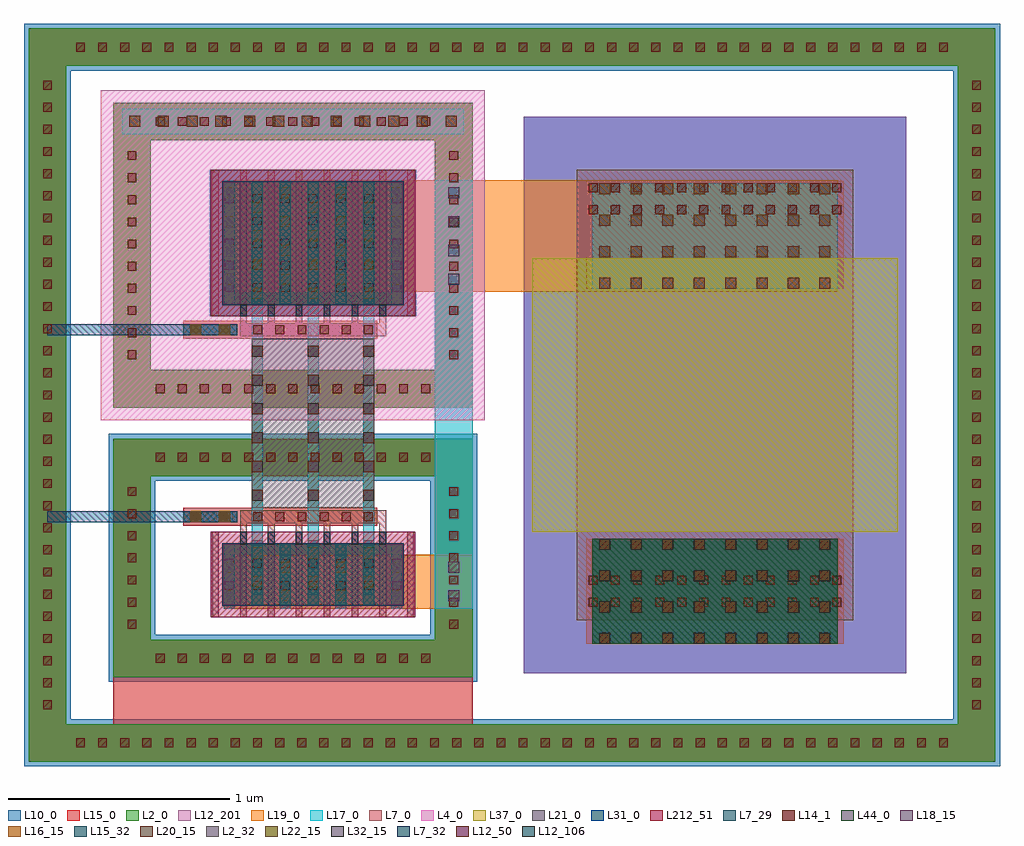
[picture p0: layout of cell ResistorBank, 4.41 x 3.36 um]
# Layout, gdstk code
import gdstk
lib = gdstk.Library(unit=1e-6, precision=1e-09)
def R(c, l, rs):  # rectangles x0, y0, x1, y1
    for r in rs: c.add(gdstk.rectangle(r[:2], r[2:], *l))
def A(c, l, x, y, w, h, nx, ny, dx, dy):  # array of equal rectangles
    R(c, l, [(x+i*dx, y+j*dy, x+i*dx+w, y+j*dy+h) for i in range(nx) for j in range(ny)])
def P(c, l, *ps):  # polygons
    for p in ps: c.add(gdstk.Polygon(p, *l))
L2_0 = (2, 0)
L2_32 = (2, 32)
L4_0 = (4, 0)
L7_0 = (7, 0)
L7_29 = (7, 29)
L7_32 = (7, 32)
L10_0 = (10, 0)
L12_50 = (12, 50)
L12_106 = (12, 106)
L12_201 = (12, 201)
L14_1 = (14, 1)
L15_0 = (15, 0)
L15_32 = (15, 32)
L16_15 = (16, 15)
L17_0 = (17, 0)
L18_15 = (18, 15)
L19_0 = (19, 0)
L20_15 = (20, 15)
L21_0 = (21, 0)
L22_15 = (22, 15)
L31_0 = (31, 0)
L32_15 = (32, 15)
L37_0 = (37, 0)
L44_0 = (44, 0)
L212_51 = (212, 51)

viamet12met2oninputinres = lib.new_cell('ViaMet12Met2OnInputInResistorBank')
R(viamet12met2oninputinres, L15_0, [(-0.122,-0.025,0.122,0.025)])
R(viamet12met2oninputinres, L16_15, [(-0.09,-0.025,-0.04,0.025), (0.04,-0.025,0.09,0.025)])
R(viamet12met2oninputinres, L17_0, [(-0.122,-0.025,0.122,0.025)])

viamet12met2onvddinresis = lib.new_cell('ViaMet12Met2OnVDDInResistorBank')
R(viamet12met2onvddinresis, L15_0, [(-0.772,-0.057,0.772,0.057)])
A(viamet12met2onvddinresis, L16_15, -0.74, -0.025, 0.05, 0.05, 12, 1, 0.13, 0)
R(viamet12met2onvddinresis, L17_0, [(-0.772,-0.057,0.772,0.057)])

viavcmmet22met3inresisto = lib.new_cell('ViaVCMMet22Met3InResistorBank')
R(viavcmmet22met3inresisto, L17_0, [(-0.025,-0.382,0.025,0.382)])
A(viavcmmet22met3inresisto, L18_15, -0.025, -0.35, 0.05, 0.05, 1, 6, 0, 0.13)
R(viavcmmet22met3inresisto, L19_0, [(-0.025,-0.382,0.025,0.382)])

viamet52met6onresistorin = lib.new_cell('ViaMet52Met6OnResistorInResistorBank')
R(viamet52met6onresistorin, L31_0, [(-0.554,-0.238,0.554,0.238)])
A(viamet52met6onresistorin, L32_15, -0.522, -0.238, 0.05, 0.05, 8, 4, 0.142, 0.142)
R(viamet52met6onresistorin, L44_0, [(-0.554,-0.238,0.554,0.238)])

viatgnmos2resmet22met3in = lib.new_cell('ViaTGNMOS2ResMet22Met3InResistorBank')
R(viatgnmos2resmet22met3in, L17_0, [(-0.057,-0.09,0.057,0.09)])
R(viatgnmos2resmet22met3in, L18_15, [(-0.025,-0.09,0.025,-0.04), (-0.025,0.04,0.025,0.09)])
R(viatgnmos2resmet22met3in, L19_0, [(-0.057,-0.09,0.057,0.09)])

viamet32met4oninputinres = lib.new_cell('ViaMet32Met4OnInputInResistorBank')
R(viamet32met4oninputinres, L19_0, [(-0.122,-0.025,0.122,0.025)])
R(viamet32met4oninputinres, L20_15, [(-0.09,-0.025,-0.04,0.025), (0.04,-0.025,0.09,0.025)])
R(viamet32met4oninputinres, L21_0, [(-0.122,-0.025,0.122,0.025)])

viamet22met3oninputinres = lib.new_cell('ViaMet22Met3OnInputInResistorBank')
R(viamet22met3oninputinres, L17_0, [(-0.122,-0.025,0.122,0.025)])
R(viamet22met3oninputinres, L18_15, [(-0.09,-0.025,-0.04,0.025), (0.04,-0.025,0.09,0.025)])
R(viamet22met3oninputinres, L19_0, [(-0.122,-0.025,0.122,0.025)])

viamet12met2onresistorin = lib.new_cell('ViaMet12Met2OnResistorInResistorBank')
R(viamet12met2onresistorin, L15_0, [(-0.554,-0.238,0.554,0.238)])
A(viamet12met2onresistorin, L16_15, -0.522, -0.238, 0.05, 0.05, 8, 4, 0.142, 0.142)
R(viamet12met2onresistorin, L17_0, [(-0.554,-0.238,0.554,0.238)])

nmossubringinresistorban = lib.new_cell('NMOSSubringInResistorBank')
R(nmossubringinresistorban, L2_0, [(-0.812,-0.539,-0.642,0.539), (-0.812,-0.539,0.812,-0.369), (0.642,-0.539,0.812,0.539), (-0.812,0.369,0.812,0.539)])
A(nmossubringinresistorban, L14_1, -0.62, -0.474, 0.04, 0.04, 13, 2, 0.1, 0.908)
A(nmossubringinresistorban, L14_1, -0.747, -0.32, 0.04, 0.04, 1, 7, 0, 0.1)
A(nmossubringinresistorban, L14_1, 0.707, -0.32, 0.04, 0.04, 1, 7, 0, 0.1)
R(nmossubringinresistorban, L15_0, [(-0.812,-0.539,0.812,-0.369), (-0.812,-0.539,-0.642,0.539), (0.642,-0.539,0.812,0.539), (-0.812,0.369,0.812,0.539)])
nmossubringinresistorban.add(gdstk.FlexPath([(0.727,0.56),(0.727,-0.454),(-0.727,-0.454),(-0.727,0.454),(0.833,0.454)], 0.212, ends="flush", simple_path=True, layer=10, datatype=0))  # L10_0

totalsubringinresistorba = lib.new_cell('TotalSubringInResistorBank')
R(totalsubringinresistorba, L2_0, [(-2.184,-1.657,-2.014,1.657), (-2.184,-1.657,2.184,-1.487), (2.014,-1.657,2.184,1.657), (-2.184,1.487,2.184,1.657)])
A(totalsubringinresistorba, L14_1, -1.97, -1.592, 0.04, 0.04, 40, 2, 0.1, 3.144)
A(totalsubringinresistorba, L14_1, -2.119, -1.42, 0.04, 0.04, 1, 29, 0, 0.1)
A(totalsubringinresistorba, L14_1, 2.079, -1.42, 0.04, 0.04, 1, 29, 0, 0.1)
R(totalsubringinresistorba, L15_0, [(-2.184,-1.657,2.184,-1.487), (-2.184,-1.657,-2.014,1.657), (2.014,-1.657,2.184,1.657), (-2.184,1.487,2.184,1.657)])
totalsubringinresistorba.add(gdstk.FlexPath([(2.099,1.678),(2.099,-1.572),(-2.099,-1.572),(-2.099,1.572),(2.205,1.572)], 0.212, ends="flush", simple_path=True, layer=10, datatype=0))  # L10_0

opppcresinresistorbank = lib.new_cell('OpppcresInResistorBank')
R(opppcresinresistorbank, L7_0, [(-0.625,-1.017,0.625,1.017)])
R(opppcresinresistorbank, L10_0, [(-0.865,-1.257,0.865,1.257)])
R(opppcresinresistorbank, L12_201, [(-0.865,-1.257,0.865,1.257)])
A(opppcresinresistorbank, L14_1, -0.57, -0.957, 0.04, 0.04, 12, 2, 0.1, 0.1)
A(opppcresinresistorbank, L14_1, -0.57, 0.817, 0.04, 0.04, 12, 2, 0.1, 0.1)
R(opppcresinresistorbank, L15_0, [(-0.582,-0.969,0.582,-0.805), (-0.582,0.805,0.582,0.969)])
R(opppcresinresistorbank, L37_0, [(-0.825,-0.617,0.825,0.617)])

viatgpmos2resmet22met3in = lib.new_cell('ViaTGPMOS2ResMet22Met3InResistorBank')
R(viatgpmos2resmet22met3in, L17_0, [(-0.057,-0.22,0.057,0.22)])
A(viatgpmos2resmet22met3in, L18_15, -0.025, -0.22, 0.05, 0.05, 1, 4, 0, 0.13)
R(viatgpmos2resmet22met3in, L19_0, [(-0.057,-0.22,0.057,0.22)])

viamet42met5oninputinres = lib.new_cell('ViaMet42Met5OnInputInResistorBank')
R(viamet42met5oninputinres, L21_0, [(-0.122,-0.025,0.122,0.025)])
R(viamet42met5oninputinres, L22_15, [(-0.09,-0.025,-0.04,0.025), (0.04,-0.025,0.09,0.025)])
R(viamet42met5oninputinres, L31_0, [(-0.122,-0.025,0.122,0.025)])

pmossubringinresistorban = lib.new_cell('PMOSSubringInResistorBank')
R(pmossubringinresistorban, L2_0, [(-0.812,-0.689,-0.642,0.689), (-0.812,-0.689,0.812,-0.519), (0.642,-0.689,0.812,0.689), (-0.812,0.519,0.812,0.689)])
A(pmossubringinresistorban, L14_1, -0.62, -0.624, 0.04, 0.04, 13, 2, 0.1, 1.208)
A(pmossubringinresistorban, L14_1, -0.747, -0.47, 0.04, 0.04, 1, 10, 0, 0.1)
A(pmossubringinresistorban, L14_1, 0.707, -0.47, 0.04, 0.04, 1, 10, 0, 0.1)
R(pmossubringinresistorban, L15_0, [(-0.812,-0.689,0.812,-0.519), (-0.812,-0.689,-0.642,0.689), (0.642,-0.689,0.812,0.689), (-0.812,0.519,0.812,0.689)])
pmossubringinresistorban.add(gdstk.FlexPath([(0.727,0.745),(0.727,-0.604),(-0.727,-0.604),(-0.727,0.604),(0.868,0.604)], 0.282, ends="flush", simple_path=True, layer=4, datatype=0))  # L4_0

viavcmmet32met4inresisto = lib.new_cell('ViaVCMMet32Met4InResistorBank')
R(viavcmmet32met4inresisto, L19_0, [(-0.025,-0.382,0.025,0.382)])
A(viavcmmet32met4inresisto, L20_15, -0.025, -0.35, 0.05, 0.05, 1, 6, 0, 0.13)
R(viavcmmet32met4inresisto, L21_0, [(-0.025,-0.382,0.025,0.382)])

viamet12met2onnmosoutput = lib.new_cell('ViaMet12Met2OnNMOSOutputInTransmissionGate')
R(viamet12met2onnmosoutput, L15_0, [(-0.025,-0.122,0.025,0.122)])
R(viamet12met2onnmosoutput, L16_15, [(-0.025,-0.09,0.025,-0.04), (-0.025,0.04,0.025,0.09)])
R(viamet12met2onnmosoutput, L17_0, [(-0.025,-0.122,0.025,0.122)])

pmosintransmissiongate = lib.new_cell('PMOSInTransmissionGate')
R(pmosintransmissiongate, L2_0, [(-0.406,-0.275,0.406,0.275)])
R(pmosintransmissiongate, L2_32, [(-0.406,-0.275,-0.33,0.275), (0.33,-0.275,0.406,0.275)])
A(pmosintransmissiongate, L7_0, -0.456, -0.331, 0.03, 0.662, 8, 1, 0.126, 0)
R(pmosintransmissiongate, L7_29, [(-0.411,-0.28,0.411,0.28)])
A(pmosintransmissiongate, L7_32, -0.33, -0.331, 0.03, 0.056, 6, 1, 0.126, 0)
R(pmosintransmissiongate, L10_0, [(-0.466,-0.331,0.466,0.331)])
P(pmosintransmissiongate, L12_50, [(0,0),(0,0),(0,0),(0,0)])
P(pmosintransmissiongate, L12_106, [(0,0),(0,0),(0,0),(0,0)])
A(pmosintransmissiongate, L14_1, -0.398, -0.22, 0.04, 0.04, 7, 5, 0.126, 0.1)
A(pmosintransmissiongate, L15_0, -0.403, -0.275, 0.05, 0.55, 7, 1, 0.126, 0)
A(pmosintransmissiongate, L15_32, -0.403, -0.275, 0.05, 0.55, 7, 1, 0.126, 0)
R(pmosintransmissiongate, L212_51, [(-0.462,-0.331,0.462,0.331)])

viamet22met3onnmosoutput = lib.new_cell('ViaMet22Met3OnNMOSOutputInTransmissionGate')
R(viamet22met3onnmosoutput, L17_0, [(-0.025,-0.122,0.025,0.122)])
R(viamet22met3onnmosoutput, L18_15, [(-0.025,-0.09,0.025,-0.04), (-0.025,0.04,0.025,0.09)])
R(viamet22met3onnmosoutput, L19_0, [(-0.025,-0.122,0.025,0.122)])

viapoly2met1onnmoscontro = lib.new_cell('ViaPoly2Met1OnNMOSControlInTransmissionGate')
R(viapoly2met1onnmoscontro, L7_0, [(-0.28,-0.03,0.28,0.03)])
A(viapoly2met1onnmoscontro, L14_1, -0.27, -0.02, 0.04, 0.04, 6, 1, 0.1, 0)
R(viapoly2met1onnmoscontro, L15_0, [(-0.291,-0.041,0.291,0.041)])

viamet12met2onpmosoutput = lib.new_cell('ViaMet12Met2OnPMOSOutputInTransmissionGate')
R(viamet12met2onpmosoutput, L15_0, [(-0.025,-0.252,0.025,0.252)])
A(viamet12met2onpmosoutput, L16_15, -0.025, -0.22, 0.05, 0.05, 1, 4, 0, 0.13)
R(viamet12met2onpmosoutput, L17_0, [(-0.025,-0.252,0.025,0.252)])

viapoly2met1onpmoscontro = lib.new_cell('ViaPoly2Met1OnPMOSControlInTransmissionGate')
R(viapoly2met1onpmoscontro, L7_0, [(-0.28,-0.03,0.28,0.03)])
A(viapoly2met1onpmoscontro, L14_1, -0.27, -0.02, 0.04, 0.04, 6, 1, 0.1, 0)
R(viapoly2met1onpmoscontro, L15_0, [(-0.291,-0.041,0.291,0.041)])

viamet22met3onpmosoutput = lib.new_cell('ViaMet22Met3OnPMOSOutputInTransmissionGate')
R(viamet22met3onpmosoutput, L17_0, [(-0.025,-0.252,0.025,0.252)])
A(viamet22met3onpmosoutput, L18_15, -0.025, -0.22, 0.05, 0.05, 1, 4, 0, 0.13)
R(viamet22met3onpmosoutput, L19_0, [(-0.025,-0.252,0.025,0.252)])

nmosintransmissiongate = lib.new_cell('NMOSInTransmissionGate')
R(nmosintransmissiongate, L2_0, [(-0.406,-0.137,0.406,0.137)])
R(nmosintransmissiongate, L2_32, [(-0.406,-0.137,-0.33,0.137), (0.33,-0.137,0.406,0.137)])
A(nmosintransmissiongate, L7_0, -0.456, -0.193, 0.03, 0.386, 8, 1, 0.126, 0)
R(nmosintransmissiongate, L7_29, [(-0.411,-0.142,0.411,0.142)])
A(nmosintransmissiongate, L7_32, -0.33, -0.193, 0.03, 0.056, 6, 1, 0.126, 0)
P(nmosintransmissiongate, L12_50, [(0,0),(0,0),(0,0),(0,0)])
P(nmosintransmissiongate, L12_106, [(0,0),(0,0),(0,0),(0,0)])
A(nmosintransmissiongate, L14_1, -0.398, -0.07, 0.04, 0.04, 7, 2, 0.126, 0.1)
A(nmosintransmissiongate, L15_0, -0.403, -0.137, 0.05, 0.274, 7, 1, 0.126, 0)
A(nmosintransmissiongate, L15_32, -0.403, -0.137, 0.05, 0.274, 7, 1, 0.126, 0)
R(nmosintransmissiongate, L212_51, [(-0.462,-0.193,0.462,0.193)])

transmissiongateinresist = lib.new_cell('TransmissionGateInResistorBank')
transmissiongateinresist.add(gdstk.FlexPath([(-0.315,0.64),(0.315,0.64)], 0.06, ends="flush", simple_path=True, layer=7, datatype=0))  # L7_0
transmissiongateinresist.add(gdstk.FlexPath([(-0.315,0.379),(-0.315,0.67)], 0.03, ends="flush", simple_path=True, layer=7, datatype=0))  # L7_0
transmissiongateinresist.add(gdstk.FlexPath([(-0.189,0.379),(-0.189,0.67)], 0.03, ends="flush", simple_path=True, layer=7, datatype=0))  # L7_0
transmissiongateinresist.add(gdstk.FlexPath([(-0.063,0.379),(-0.063,0.67)], 0.03, ends="flush", simple_path=True, layer=7, datatype=0))  # L7_0
transmissiongateinresist.add(gdstk.FlexPath([(0.063,0.379),(0.063,0.67)], 0.03, ends="flush", simple_path=True, layer=7, datatype=0))  # L7_0
transmissiongateinresist.add(gdstk.FlexPath([(0.189,0.379),(0.189,0.67)], 0.03, ends="flush", simple_path=True, layer=7, datatype=0))  # L7_0
transmissiongateinresist.add(gdstk.FlexPath([(0.315,0.379),(0.315,0.67)], 0.03, ends="flush", simple_path=True, layer=7, datatype=0))  # L7_0
transmissiongateinresist.add(gdstk.FlexPath([(-0.315,1.876),(-0.315,1.455)], 0.03, ends="flush", simple_path=True, layer=7, datatype=0))  # L7_0
transmissiongateinresist.add(gdstk.FlexPath([(-0.189,1.876),(-0.189,1.455)], 0.03, ends="flush", simple_path=True, layer=7, datatype=0))  # L7_0
transmissiongateinresist.add(gdstk.FlexPath([(-0.063,1.876),(-0.063,1.455)], 0.03, ends="flush", simple_path=True, layer=7, datatype=0))  # L7_0
transmissiongateinresist.add(gdstk.FlexPath([(0.063,1.876),(0.063,1.455)], 0.03, ends="flush", simple_path=True, layer=7, datatype=0))  # L7_0
transmissiongateinresist.add(gdstk.FlexPath([(0.189,1.876),(0.189,1.455)], 0.03, ends="flush", simple_path=True, layer=7, datatype=0))  # L7_0
transmissiongateinresist.add(gdstk.FlexPath([(0.315,1.876),(0.315,1.455)], 0.03, ends="flush", simple_path=True, layer=7, datatype=0))  # L7_0
transmissiongateinresist.add(gdstk.FlexPath([(-0.315,1.485),(0.315,1.485)], 0.06, ends="flush", simple_path=True, layer=7, datatype=0))  # L7_0
transmissiongateinresist.add(gdstk.Reference(viamet12met2onnmosoutput, (-0.252,0.411)))
transmissiongateinresist.add(gdstk.Reference(viamet12met2onnmosoutput, (0,0.411)))
transmissiongateinresist.add(gdstk.Reference(viamet12met2onnmosoutput, (0.252,0.411)))
transmissiongateinresist.add(gdstk.Reference(viamet12met2onnmosoutput, (-0.378,0.347)))
transmissiongateinresist.add(gdstk.Reference(viamet12met2onnmosoutput, (-0.126,0.347)))
transmissiongateinresist.add(gdstk.Reference(viamet12met2onnmosoutput, (0.126,0.347)))
transmissiongateinresist.add(gdstk.Reference(viamet12met2onnmosoutput, (0.378,0.347)))
transmissiongateinresist.add(gdstk.Reference(pmosintransmissiongate, (0,1.876)))
transmissiongateinresist.add(gdstk.Reference(viamet22met3onnmosoutput, (-0.378,0.347)))
transmissiongateinresist.add(gdstk.Reference(viamet22met3onnmosoutput, (-0.126,0.347)))
transmissiongateinresist.add(gdstk.Reference(viamet22met3onnmosoutput, (0.126,0.347)))
transmissiongateinresist.add(gdstk.Reference(viamet22met3onnmosoutput, (0.378,0.347)))
transmissiongateinresist.add(gdstk.Reference(viapoly2met1onnmoscontro, (0,0.64)))
transmissiongateinresist.add(gdstk.Reference(viamet12met2onpmosoutput, (-0.252,1.844)))
transmissiongateinresist.add(gdstk.Reference(viamet12met2onpmosoutput, (0,1.844)))
transmissiongateinresist.add(gdstk.Reference(viamet12met2onpmosoutput, (0.252,1.844)))
transmissiongateinresist.add(gdstk.Reference(viamet12met2onpmosoutput, (-0.378,1.908)))
transmissiongateinresist.add(gdstk.Reference(viamet12met2onpmosoutput, (-0.126,1.908)))
transmissiongateinresist.add(gdstk.Reference(viamet12met2onpmosoutput, (0.126,1.908)))
transmissiongateinresist.add(gdstk.Reference(viamet12met2onpmosoutput, (0.378,1.908)))
transmissiongateinresist.add(gdstk.Reference(viapoly2met1onpmoscontro, (0,1.485)))
transmissiongateinresist.add(gdstk.Reference(viamet22met3onpmosoutput, (-0.378,1.908)))
transmissiongateinresist.add(gdstk.Reference(viamet22met3onpmosoutput, (-0.126,1.908)))
transmissiongateinresist.add(gdstk.Reference(viamet22met3onpmosoutput, (0.126,1.908)))
transmissiongateinresist.add(gdstk.Reference(viamet22met3onpmosoutput, (0.378,1.908)))
transmissiongateinresist.add(gdstk.Reference(nmosintransmissiongate, (0,0.379), x_reflection=True))

viamet22met3onresistorin = lib.new_cell('ViaMet22Met3OnResistorInResistorBank')
R(viamet22met3onresistorin, L17_0, [(-0.554,-0.238,0.554,0.238)])
A(viamet22met3onresistorin, L18_15, -0.522, -0.238, 0.05, 0.05, 8, 4, 0.142, 0.142)
R(viamet22met3onresistorin, L19_0, [(-0.554,-0.238,0.554,0.238)])

viamet32met4onresistorin = lib.new_cell('ViaMet32Met4OnResistorInResistorBank')
R(viamet32met4onresistorin, L19_0, [(-0.554,-0.238,0.554,0.238)])
A(viamet32met4onresistorin, L20_15, -0.522, -0.238, 0.05, 0.05, 8, 4, 0.142, 0.142)
R(viamet32met4onresistorin, L21_0, [(-0.554,-0.238,0.554,0.238)])

viamet42met5onresistorin = lib.new_cell('ViaMet42Met5OnResistorInResistorBank')
R(viamet42met5onresistorin, L21_0, [(-0.554,-0.238,0.554,0.238)])
A(viamet42met5onresistorin, L22_15, -0.522, -0.238, 0.05, 0.05, 8, 4, 0.142, 0.142)
R(viamet42met5onresistorin, L31_0, [(-0.554,-0.238,0.554,0.238)])

viamet22met3onvddinresis = lib.new_cell('ViaMet22Met3OnVDDInResistorBank')
R(viamet22met3onvddinresis, L17_0, [(-0.772,-0.057,0.772,0.057)])
A(viamet22met3onvddinresis, L18_15, -0.74, -0.025, 0.05, 0.05, 12, 1, 0.13, 0)
R(viamet22met3onvddinresis, L19_0, [(-0.772,-0.057,0.772,0.057)])

resistorbank = lib.new_cell('ResistorBank')
R(resistorbank, L15_0, [(-0.903,-0.467,0.721,0.085)])
A(resistorbank, L17_0, -0.277, 0.288, 0.05, 1.807, 3, 1, 0.252, 0)
R(resistorbank, L21_0, [(-0.252,0.68,0.252,1.444)])
resistorbank.add(gdstk.FlexPath([(0.636,2.16),(0.636,0.225)], 0.17, ends="flush", simple_path=True, layer=17, datatype=0))  # L17_0
resistorbank.add(gdstk.FlexPath([(-0.378,1.908),(2.37,1.908)], 0.504, ends="flush", simple_path=True, layer=19, datatype=0))  # L19_0
resistorbank.add(gdstk.FlexPath([(-0.587,1.485),(0,1.485)], 0.082, ends="flush", simple_path=True, layer=15, datatype=0))  # L15_0
resistorbank.add(gdstk.FlexPath([(-0.587,0.64),(0,0.64)], 0.082, ends="flush", simple_path=True, layer=15, datatype=0))  # L15_0
resistorbank.add(gdstk.FlexPath([(-0.733,1.822),(0.551,1.822)], 1.038, ends="flush", simple_path=True, layer=4, datatype=0))  # L4_0
resistorbank.add(gdstk.FlexPath([(-0.465,1.485),(-1.2,1.485)], 0.05, ends="flush", simple_path=True, layer=31, datatype=0))  # L31_0
resistorbank.add(gdstk.FlexPath([(-0.465,0.64),(-1.2,0.64)], 0.05, ends="flush", simple_path=True, layer=31, datatype=0))  # L31_0
resistorbank.add(gdstk.FlexPath([(-0.378,0.347),(0.721,0.347)], 0.244, ends="flush", simple_path=True, layer=19, datatype=0))  # L19_0
resistorbank.add(gdstk.FlexPath([(1.816,1.67),(1.816,2.159)], 1.164, ends="flush", simple_path=True, layer=15, datatype=0))  # L15_0
resistorbank.add(gdstk.FlexPath([(1.816,0.541),(1.816,0.065)], 1.164, ends="flush", simple_path=True, layer=15, datatype=0))  # L15_0
resistorbank.add(gdstk.Reference(viamet12met2oninputinres, (-0.465,1.485)))
resistorbank.add(gdstk.Reference(viamet12met2oninputinres, (-0.465,0.64)))
resistorbank.add(gdstk.Reference(viamet12met2onvddinresis, (-0.091,2.426)))
resistorbank.add(gdstk.Reference(viavcmmet22met3inresisto, (-0.252,1.062)))
resistorbank.add(gdstk.Reference(viavcmmet22met3inresisto, (0,1.062)))
resistorbank.add(gdstk.Reference(viavcmmet22met3inresisto, (0.252,1.062)))
resistorbank.add(gdstk.Reference(viamet52met6onresistorin, (1.816,0.303)))
resistorbank.add(gdstk.Reference(viatgnmos2resmet22met3in, (0.636,0.347)))
resistorbank.add(gdstk.Reference(viamet32met4oninputinres, (-0.465,1.485)))
resistorbank.add(gdstk.Reference(viamet32met4oninputinres, (-0.465,0.64)))
resistorbank.add(gdstk.Reference(viamet22met3oninputinres, (-0.465,1.485)))
resistorbank.add(gdstk.Reference(viamet22met3oninputinres, (-0.465,0.64)))
resistorbank.add(gdstk.Reference(viamet12met2onresistorin, (1.816,1.908)))
resistorbank.add(gdstk.Reference(viamet12met2onresistorin, (1.816,0.303)))
resistorbank.add(gdstk.Reference(nmossubringinresistorban, (-0.091,0.454)))
resistorbank.add(gdstk.Reference(totalsubringinresistorba, (0.899,1.19)))
resistorbank.add(gdstk.Reference(opppcresinresistorbank, (1.816,1.19)))
resistorbank.add(gdstk.Reference(viatgpmos2resmet22met3in, (0.636,1.908)))
resistorbank.add(gdstk.Reference(viamet42met5oninputinres, (-0.465,1.485)))
resistorbank.add(gdstk.Reference(viamet42met5oninputinres, (-0.465,0.64)))
resistorbank.add(gdstk.Reference(pmossubringinresistorban, (-0.091,1.822)))
resistorbank.add(gdstk.Reference(viavcmmet32met4inresisto, (-0.252,1.062)))
resistorbank.add(gdstk.Reference(viavcmmet32met4inresisto, (0,1.062)))
resistorbank.add(gdstk.Reference(viavcmmet32met4inresisto, (0.252,1.062)))
resistorbank.add(gdstk.Reference(transmissiongateinresist, (0,0)))
resistorbank.add(gdstk.Reference(viamet22met3onresistorin, (1.816,1.908)))
resistorbank.add(gdstk.Reference(viamet22met3onresistorin, (1.816,0.303)))
resistorbank.add(gdstk.Reference(viamet32met4onresistorin, (1.816,0.303)))
resistorbank.add(gdstk.Reference(viamet42met5onresistorin, (1.816,0.303)))
resistorbank.add(gdstk.Reference(viamet22met3onvddinresis, (-0.091,2.426)))

lib.write_gds('ResistorBank.gds')
